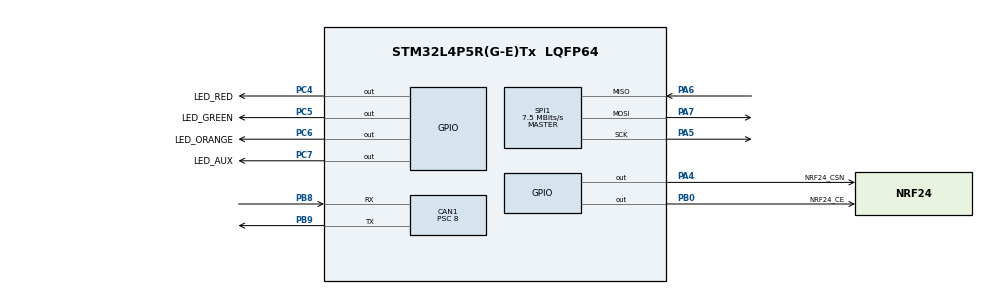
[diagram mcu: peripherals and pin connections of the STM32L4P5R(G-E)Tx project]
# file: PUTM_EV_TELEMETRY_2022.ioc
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ADC1.Channel-0\#ChannelRegularConversion=ADC_CHANNEL_VBAT
ADC1.NbrOfConversionFlag=1
ADC1.OffsetNumber-0\#ChannelRegularConversion=ADC_OFFSET_NONE
ADC1.Rank-0\#ChannelRegularConversion=1
ADC1.SamplingTime-0\#ChannelRegularConversion=ADC_SAMPLETIME_2CYCLES_5
ADC1.master=1
CAN1.BS1=CAN_BS1_12TQ
CAN1.BS2=CAN_BS2_2TQ
CAN1.CalculateBaudRate=999999
CAN1.CalculateTimeBit=1000
CAN1.CalculateTimeQuantum=66.66666666666667
CAN1.Mode=CAN_MODE_NORMAL
CAN1.Prescaler=8
CAN1.SJW=CAN_SJW_1TQ
Mcu.Family=STM32L4
Mcu.Name=STM32L4P5R(G-E)Tx
Mcu.Package=LQFP64
NVIC.CAN1_RX0_IRQn=true\:1\:0\:true\:false\:true\:true\:true\:true
NVIC.PriorityGroup=NVIC_PRIORITYGROUP_4
NVIC.TIM2_IRQn=true\:0\:0\:false\:false\:true\:true\:true\:true
NVIC.TIM3_IRQn=true\:0\:0\:false\:false\:true\:true\:true\:true
NVIC.TIM4_IRQn=true\:0\:0\:false\:false\:true\:true\:true\:true
NVIC.TIM5_IRQn=true\:0\:0\:false\:false\:true\:true\:true\:true
NVIC.TIM6_DAC_IRQn=true\:0\:0\:false\:false\:true\:true\:true\:true
PA13\ (JTMS/SWDIO).Mode=JTAG_5_pins
PA13\ (JTMS/SWDIO).Signal=SYS_JTMS-SWDIO
PA14\ (JTCK/SWCLK).Mode=JTAG_5_pins
PA14\ (JTCK/SWCLK).Signal=SYS_JTCK-SWCLK
PA15\ (JTDI).Mode=JTAG_5_pins
PA15\ (JTDI).Signal=SYS_JTDI
PA4.GPIO_Label=NRF24_CSN
PA4.Signal=GPIO_Output
PA5.Mode=Full_Duplex_Master
PA5.Signal=SPI1_SCK
PA6.Mode=Full_Duplex_Master
PA6.Signal=SPI1_MISO
PA7.Mode=Full_Duplex_Master
PA7.Signal=SPI1_MOSI
PB0.GPIO_Label=NRF24_CE
PB0.Signal=GPIO_Output
PB3\ (JTDO/TRACESWO).Mode=JTAG_5_pins
PB3\ (JTDO/TRACESWO).Signal=SYS_JTDO-SWO
PB4\ (NJTRST).Mode=JTAG_5_pins
PB4\ (NJTRST).Signal=SYS_JTRST
PB8.Mode=CAN_Activate
PB8.Signal=CAN1_RX
PB9.Mode=CAN_Activate
PB9.Signal=CAN1_TX
PC14-OSC32_IN\ (PC14).Signal=RCC_OSC32_IN
PC15-OSC32_OUT\ (PC15).Signal=RCC_OSC32_OUT
PC4.GPIO_Label=LED_RED
PC4.Signal=GPIO_Output
PC5.GPIO_Label=LED_GREEN
PC5.Signal=GPIO_Output
PC6.GPIO_Label=LED_ORANGE
PC6.Signal=GPIO_Output
PC7.GPIO_Label=LED_AUX
PC7.Signal=GPIO_Output
PH0-OSC_IN\ (PH0).Mode=HSE-External-Oscillator
PH0-OSC_IN\ (PH0).Signal=RCC_OSC_IN
PH1-OSC_OUT\ (PH1).Mode=HSE-External-Oscillator
PH1-OSC_OUT\ (PH1).Signal=RCC_OSC_OUT
ProjectManager.HeapSize=0x200
ProjectManager.StackSize=0x400
ProjectManager.TargetToolchain=STM32CubeIDE
RCC.ADCFreq_Value=32000000
RCC.AHBFreq_Value=120000000
RCC.APB1Freq_Value=120000000
RCC.APB1TimFreq_Value=120000000
RCC.APB2Freq_Value=120000000
RCC.APB2TimFreq_Value=120000000
RCC.CortexFreq_Value=120000000
RCC.HCLKFreq_Value=120000000
RCC.HSE_VALUE=24576000
RCC.HSI48_VALUE=48000000
RCC.HSI_VALUE=16000000
RCC.LSE_VALUE=32768
RCC.MSI_VALUE=4000000
RCC.PLLN=60
RCC.PLLSAI1N=16
RCC.PREFETCH_ENABLE=1
RCC.SYSCLKFreq_VALUE=120000000
RCC.SYSCLKSource=RCC_SYSCLKSOURCE_PLLCLK
RCC.USBFreq_Value=32000000
RCC.VCOOutputFreq_Value=240000000
RTC.Format=RTC_FORMAT_BIN
RTC.Hours=17
RTC.Minutes=13
SPI1.BaudRatePrescaler=SPI_BAUDRATEPRESCALER_16
SPI1.CalculateBaudRate=7.5 MBits/s
SPI1.DataSize=SPI_DATASIZE_8BIT
SPI1.Direction=SPI_DIRECTION_2LINES
SPI1.Mode=SPI_MODE_MASTER
SPI1.VirtualType=VM_MASTER
TIM2.AutoReloadPreload=TIM_AUTORELOAD_PRELOAD_ENABLE
TIM2.Period=10000
TIM2.Prescaler=12000-1
TIM3.AutoReloadPreload=TIM_AUTORELOAD_PRELOAD_ENABLE
TIM3.Period=100
TIM3.Prescaler=12000-1
TIM4.AutoReloadPreload=TIM_AUTORELOAD_PRELOAD_ENABLE
TIM4.Period=200
TIM4.Prescaler=12000-1
TIM5.AutoReloadPreload=TIM_AUTORELOAD_PRELOAD_ENABLE
TIM5.Period=300
TIM5.Prescaler=12000-1
TIM6.AutoReloadPreload=TIM_AUTORELOAD_PRELOAD_ENABLE
TIM6.Period=5000
TIM6.Prescaler=1200-1
TIM7.AutoReloadPreload=TIM_AUTORELOAD_PRELOAD_ENABLE
TIM7.Prescaler=120-1
VP_ADC1_Vbat_Input.Mode=IN-Vbat
VP_RTC_VS_RTC_Activate.Mode=RTC_Enabled
VP_RTC_VS_RTC_Calendar.Mode=RTC_Calendar
VP_TIM2_VS_ClockSourceINT.Mode=Internal
VP_TIM3_VS_ClockSourceINT.Mode=Internal
VP_TIM4_VS_ClockSourceINT.Mode=Internal
VP_TIM5_VS_ClockSourceINT.Mode=Internal
VP_TIM6_VS_ClockSourceINT.Mode=Enable_Timer
VP_TIM7_VS_ClockSourceINT.Mode=Enable_Timer
board=custom

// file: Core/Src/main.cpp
/* USER CODE BEGIN Header */
/**
 ******************************************************************************
 * @file           : main.c
 * @brief          : Main program body
 ******************************************************************************
 * @attention
 *
 * <h2><center>&copy; Copyright (c) 2022 STMicroelectronics.
 * All rights reserved.</center></h2>
 *
 * This software component is licensed by ST under BSD 3-Clause license,
 * the "License"; You may not use this file except in compliance with the
 * License. You may obtain a copy of the License at:
 *                        opensource.org/licenses/BSD-3-Clause
 *
 ******************************************************************************
 */
/* USER CODE END Header */
#include "main.h"

/* USER CODE BEGIN Includes */
#include "Data_Handling.hpp"
#include "LEDs.hpp"
#include "Radio_Control.hpp"
#include "etl/circular_buffer.h"
#include <vector>
/* USER CODE END Includes */

/* USER CODE BEGIN PTD */
CAN_FilterTypeDef flitr1;
CAN_RxHeaderTypeDef RxHeader_CAN1;
/* USER CODE END PTD */

ADC_HandleTypeDef hadc1;

CAN_HandleTypeDef hcan1;

RTC_HandleTypeDef hrtc;

SPI_HandleTypeDef hspi1;

TIM_HandleTypeDef htim2;
TIM_HandleTypeDef htim3;
TIM_HandleTypeDef htim4;
TIM_HandleTypeDef htim5;
TIM_HandleTypeDef htim6;
TIM_HandleTypeDef htim7;

void SystemClock_Config(void);
static void MX_GPIO_Init(void);
static void MX_CAN1_Init(void);
static void MX_SPI1_Init(void);
static void MX_TIM2_Init(void);
static void MX_RTC_Init(void);
static void MX_ADC1_Init(void);
static void MX_TIM3_Init(void);
static void MX_TIM4_Init(void);
static void MX_TIM5_Init(void);
static void MX_TIM6_Init(void);
static void MX_TIM7_Init(void);

/* USER CODE BEGIN 0 */
Data_management handler1;
HeartBeat hb1;
const bool Frame_By_Frame = false;
/* USER CODE END 0 */

int main(void)
{

  /* MCU Configuration--------------------------------------------------------*/

  /* Reset of all peripherals, Initializes the Flash interface and the Systick. */
  HAL_Init();

  /* Configure the system clock */
  SystemClock_Config();

  /* Initialize all configured peripherals */
  MX_GPIO_Init();
  MX_CAN1_Init();
  MX_SPI1_Init();
  MX_TIM2_Init();
  MX_RTC_Init();
  MX_ADC1_Init();
  MX_TIM3_Init();
  MX_TIM4_Init();
  MX_TIM5_Init();
  MX_TIM6_Init();
  MX_TIM7_Init();
  /* USER CODE BEGIN 2 */

    Clear_All();

    Start();

    Open_Filter();

    CAN_Init();

    if (Setup_Radio_As_Transmiter() == false)
    {
        Set_Error();
        Set_All();
        Error_Handler();
        //handler1.Pass_States(RADIO_ERROR);
    }
    else
    {
        Set_OK();
    }

    if (Frame_By_Frame == true)
    {
        // HAL_TIM_Base_Start_IT(&htim2);
        hb1 = HeartBeat::FRAME_BY_FRAME;
    }
    else
    {
        //HAL_TIM_Base_Start_IT(&htim2);
        HAL_TIM_Base_Start_IT(&htim3);
        HAL_TIM_Base_Start_IT(&htim4);
        HAL_TIM_Base_Start_IT(&htim5);
        HAL_TIM_Base_Start_IT(&htim6);
        hb1 = HeartBeat::DEFAULT;
    }
  /* USER CODE END 2 */

  /* Infinite loop */
    while (1)
    {

    /* USER CODE BEGIN 3 */
        /*
         * Regular state of the code, used to receive, pack and send data
         */

        switch (hb1)
        {
            case HeartBeat::Buffer1:

                Send_Data(handler1.Check_Buffer100hz());
                HAL_Delay(1);
                Send_Data(handler1.Check_Buffer_Aq());
                HAL_Delay(1);
                handler1.Clear_msg1();
                break;

            case HeartBeat::Buffer2:

                Send_Data(handler1.Check_Buffer50hz());
                HAL_Delay(1);
                break;

            case HeartBeat::Buffer3:

                Send_Data(handler1.Check_Buffer10hz());
                HAL_Delay(1);
            	if(handler1.timer_buffer.size() > 0)
            	{
            		Send_Data(handler1.timer_buffer.back());
            		handler1.timer_buffer.pop_back();
            	}
                break;

            case HeartBeat::Buffer4:

            	Send_Data(handler1.Check_Buffer1hz());
            	HAL_Delay(1);

            case HeartBeat::DEFAULT:

                break;
        }
    }
  /* USER CODE END 3 */
}

void SystemClock_Config(void)
{
  RCC_OscInitTypeDef RCC_OscInitStruct = {0};
  RCC_ClkInitTypeDef RCC_ClkInitStruct = {0};

  /** Configure the main internal regulator output voltage
  */
  if (HAL_PWREx_ControlVoltageScaling(PWR_REGULATOR_VOLTAGE_SCALE1_BOOST) != HAL_OK)
  {
    Error_Handler();
  }

  /** Initializes the RCC Oscillators according to the specified parameters
  * in the RCC_OscInitTypeDef structure.
  */
  RCC_OscInitStruct.OscillatorType = RCC_OSCILLATORTYPE_LSI|RCC_OSCILLATORTYPE_HSE;
  RCC_OscInitStruct.HSEState = RCC_HSE_ON;
  RCC_OscInitStruct.LSIState = RCC_LSI_ON;
  RCC_OscInitStruct.PLL.PLLState = RCC_PLL_ON;
  RCC_OscInitStruct.PLL.PLLSource = RCC_PLLSOURCE_HSE;
  RCC_OscInitStruct.PLL.PLLM = 4;
  RCC_OscInitStruct.PLL.PLLN = 30;
  RCC_OscInitStruct.PLL.PLLP = RCC_PLLP_DIV2;
  RCC_OscInitStruct.PLL.PLLQ = RCC_PLLQ_DIV2;
  RCC_OscInitStruct.PLL.PLLR = RCC_PLLR_DIV2;
  if (HAL_RCC_OscConfig(&RCC_OscInitStruct) != HAL_OK)
  {
    Error_Handler();
  }

  /** Initializes the CPU, AHB and APB buses clocks
  */
  RCC_ClkInitStruct.ClockType = RCC_CLOCKTYPE_HCLK|RCC_CLOCKTYPE_SYSCLK
                              |RCC_CLOCKTYPE_PCLK1|RCC_CLOCKTYPE_PCLK2;
  RCC_ClkInitStruct.SYSCLKSource = RCC_SYSCLKSOURCE_PLLCLK;
  RCC_ClkInitStruct.AHBCLKDivider = RCC_SYSCLK_DIV1;
  RCC_ClkInitStruct.APB1CLKDivider = RCC_HCLK_DIV1;
  RCC_ClkInitStruct.APB2CLKDivider = RCC_HCLK_DIV1;

  if (HAL_RCC_ClockConfig(&RCC_ClkInitStruct, FLASH_LATENCY_5) != HAL_OK)
  {
    Error_Handler();
  }
}

static void MX_ADC1_Init(void)
{

  ADC_MultiModeTypeDef multimode = {0};
  ADC_ChannelConfTypeDef sConfig = {0};

  /** Common config
  */
  hadc1.Instance = ADC1;
  hadc1.Init.ClockPrescaler = ADC_CLOCK_ASYNC_DIV1;
  hadc1.Init.Resolution = ADC_RESOLUTION_12B;
  hadc1.Init.DataAlign = ADC_DATAALIGN_RIGHT;
  hadc1.Init.ScanConvMode = ADC_SCAN_DISABLE;
  hadc1.Init.EOCSelection = ADC_EOC_SINGLE_CONV;
  hadc1.Init.LowPowerAutoWait = DISABLE;
  hadc1.Init.ContinuousConvMode = DISABLE;
  hadc1.Init.NbrOfConversion = 1;
  hadc1.Init.DiscontinuousConvMode = DISABLE;
  hadc1.Init.ExternalTrigConv = ADC_SOFTWARE_START;
  hadc1.Init.ExternalTrigConvEdge = ADC_EXTERNALTRIGCONVEDGE_NONE;
  hadc1.Init.DMAContinuousRequests = DISABLE;
  hadc1.Init.Overrun = ADC_OVR_DATA_PRESERVED;
  hadc1.Init.OversamplingMode = DISABLE;
  hadc1.Init.DFSDMConfig = ADC_DFSDM_MODE_ENABLE;
  if (HAL_ADC_Init(&hadc1) != HAL_OK)
  {
    Error_Handler();
  }

  /** Configure the ADC multi-mode
  */
  multimode.Mode = ADC_MODE_INDEPENDENT;
  if (HAL_ADCEx_MultiModeConfigChannel(&hadc1, &multimode) != HAL_OK)
  {
    Error_Handler();
  }

  /** Configure Regular Channel
  */
  sConfig.Channel = ADC_CHANNEL_VBAT;
  sConfig.Rank = ADC_REGULAR_RANK_1;
  sConfig.SamplingTime = ADC_SAMPLETIME_2CYCLES_5;
  sConfig.SingleDiff = ADC_SINGLE_ENDED;
  sConfig.OffsetNumber = ADC_OFFSET_NONE;
  sConfig.Offset = 0;
  if (HAL_ADC_ConfigChannel(&hadc1, &sConfig) != HAL_OK)
  {
    Error_Handler();
  }

}

static void MX_CAN1_Init(void)
{

  hcan1.Instance = CAN1;
  hcan1.Init.Prescaler = 8;
  hcan1.Init.Mode = CAN_MODE_NORMAL;
  hcan1.Init.SyncJumpWidth = CAN_SJW_1TQ;
  hcan1.Init.TimeSeg1 = CAN_BS1_12TQ;
  hcan1.Init.TimeSeg2 = CAN_BS2_2TQ;
  hcan1.Init.TimeTriggeredMode = DISABLE;
  hcan1.Init.AutoBusOff = DISABLE;
  hcan1.Init.AutoWakeUp = DISABLE;
  hcan1.Init.AutoRetransmission = DISABLE;
  hcan1.Init.ReceiveFifoLocked = DISABLE;
  hcan1.Init.TransmitFifoPriority = DISABLE;
  if (HAL_CAN_Init(&hcan1) != HAL_OK)
  {
    Error_Handler();
  }

}

static void MX_RTC_Init(void)
{

  RTC_TimeTypeDef sTime = {0};
  RTC_DateTypeDef sDate = {0};

  /** Initialize RTC Only
  */
  hrtc.Instance = RTC;
  hrtc.Init.HourFormat = RTC_HOURFORMAT_24;
  hrtc.Init.AsynchPrediv = 127;
  hrtc.Init.SynchPrediv = 255;
  hrtc.Init.OutPut = RTC_OUTPUT_DISABLE;
  hrtc.Init.OutPutRemap = RTC_OUTPUT_REMAP_NONE;
  hrtc.Init.OutPutPolarity = RTC_OUTPUT_POLARITY_HIGH;
  hrtc.Init.OutPutType = RTC_OUTPUT_TYPE_OPENDRAIN;
  hrtc.Init.BinMode = RTC_BINARY_NONE;
  if (HAL_RTC_Init(&hrtc) != HAL_OK)
  {
    Error_Handler();
  }

  /** Initialize RTC and set the Time and Date
  */
  sTime.Hours = 17;
  sTime.Minutes = 13;
  sTime.Seconds = 0;
  sTime.DayLightSaving = RTC_DAYLIGHTSAVING_NONE;
  sTime.StoreOperation = RTC_STOREOPERATION_RESET;
  if (HAL_RTC_SetTime(&hrtc, &sTime, RTC_FORMAT_BIN) != HAL_OK)
  {
    Error_Handler();
  }
  sDate.WeekDay = RTC_WEEKDAY_MONDAY;
  sDate.Month = RTC_MONTH_JANUARY;
  sDate.Date = 1;
  sDate.Year = 0;

  if (HAL_RTC_SetDate(&hrtc, &sDate, RTC_FORMAT_BIN) != HAL_OK)
  {
    Error_Handler();
  }

}

static void MX_SPI1_Init(void)
{

  /* SPI1 parameter configuration*/
  hspi1.Instance = SPI1;
  hspi1.Init.Mode = SPI_MODE_MASTER;
  hspi1.Init.Direction = SPI_DIRECTION_2LINES;
  hspi1.Init.DataSize = SPI_DATASIZE_8BIT;
  hspi1.Init.CLKPolarity = SPI_POLARITY_LOW;
  hspi1.Init.CLKPhase = SPI_PHASE_1EDGE;
  hspi1.Init.NSS = SPI_NSS_SOFT;
  hspi1.Init.BaudRatePrescaler = SPI_BAUDRATEPRESCALER_16;
  hspi1.Init.FirstBit = SPI_FIRSTBIT_MSB;
  hspi1.Init.TIMode = SPI_TIMODE_DISABLE;
  hspi1.Init.CRCCalculation = SPI_CRCCALCULATION_DISABLE;
  hspi1.Init.CRCPolynomial = 7;
  hspi1.Init.CRCLength = SPI_CRC_LENGTH_DATASIZE;
  hspi1.Init.NSSPMode = SPI_NSS_PULSE_ENABLE;
  if (HAL_SPI_Init(&hspi1) != HAL_OK)
  {
    Error_Handler();
  }

}

static void MX_TIM2_Init(void)
{

  TIM_ClockConfigTypeDef sClockSourceConfig = {0};
  TIM_MasterConfigTypeDef sMasterConfig = {0};

  htim2.Instance = TIM2;
  htim2.Init.Prescaler = 12000-1;
  htim2.Init.CounterMode = TIM_COUNTERMODE_UP;
  htim2.Init.Period = 10000;
  htim2.Init.ClockDivision = TIM_CLOCKDIVISION_DIV1;
  htim2.Init.AutoReloadPreload = TIM_AUTORELOAD_PRELOAD_ENABLE;
  if (HAL_TIM_Base_Init(&htim2) != HAL_OK)
  {
    Error_Handler();
  }
  sClockSourceConfig.ClockSource = TIM_CLOCKSOURCE_INTERNAL;
  if (HAL_TIM_ConfigClockSource(&htim2, &sClockSourceConfig) != HAL_OK)
  {
    Error_Handler();
  }
  sMasterConfig.MasterOutputTrigger = TIM_TRGO_RESET;
  sMasterConfig.MasterSlaveMode = TIM_MASTERSLAVEMODE_DISABLE;
  if (HAL_TIMEx_MasterConfigSynchronization(&htim2, &sMasterConfig) != HAL_OK)
  {
    Error_Handler();
  }

}

static void MX_TIM3_Init(void)
{

  TIM_ClockConfigTypeDef sClockSourceConfig = {0};
  TIM_MasterConfigTypeDef sMasterConfig = {0};

  htim3.Instance = TIM3;
  htim3.Init.Prescaler = 12000-1;
  htim3.Init.CounterMode = TIM_COUNTERMODE_UP;
  htim3.Init.Period = 100;
  htim3.Init.ClockDivision = TIM_CLOCKDIVISION_DIV1;
  htim3.Init.AutoReloadPreload = TIM_AUTORELOAD_PRELOAD_ENABLE;
  if (HAL_TIM_Base_Init(&htim3) != HAL_OK)
  {
    Error_Handler();
  }
  sClockSourceConfig.ClockSource = TIM_CLOCKSOURCE_INTERNAL;
  if (HAL_TIM_ConfigClockSource(&htim3, &sClockSourceConfig) != HAL_OK)
  {
    Error_Handler();
  }
  sMasterConfig.MasterOutputTrigger = TIM_TRGO_RESET;
  sMasterConfig.MasterSlaveMode = TIM_MASTERSLAVEMODE_DISABLE;
  if (HAL_TIMEx_MasterConfigSynchronization(&htim3, &sMasterConfig) != HAL_OK)
  {
    Error_Handler();
  }

}

static void MX_TIM4_Init(void)
{

  TIM_ClockConfigTypeDef sClockSourceConfig = {0};
  TIM_MasterConfigTypeDef sMasterConfig = {0};

  htim4.Instance = TIM4;
  htim4.Init.Prescaler = 12000-1;
  htim4.Init.CounterMode = TIM_COUNTERMODE_UP;
  htim4.Init.Period = 200;
  htim4.Init.ClockDivision = TIM_CLOCKDIVISION_DIV1;
  htim4.Init.AutoReloadPreload = TIM_AUTORELOAD_PRELOAD_ENABLE;
  if (HAL_TIM_Base_Init(&htim4) != HAL_OK)
  {
    Error_Handler();
  }
  sClockSourceConfig.ClockSource = TIM_CLOCKSOURCE_INTERNAL;
  if (HAL_TIM_ConfigClockSource(&htim4, &sClockSourceConfig) != HAL_OK)
  {
    Error_Handler();
  }
  sMasterConfig.MasterOutputTrigger = TIM_TRGO_RESET;
  sMasterConfig.MasterSlaveMode = TIM_MASTERSLAVEMODE_DISABLE;
  if (HAL_TIMEx_MasterConfigSynchronization(&htim4, &sMasterConfig) != HAL_OK)
  {
    Error_Handler();
  }

}

static void MX_TIM5_Init(void)
{

  TIM_ClockConfigTypeDef sClockSourceConfig = {0};
  TIM_MasterConfigTypeDef sMasterConfig = {0};

  htim5.Instance = TIM5;
  htim5.Init.Prescaler = 12000-1;
  htim5.Init.CounterMode = TIM_COUNTERMODE_UP;
  htim5.Init.Period = 300;
  htim5.Init.ClockDivision = TIM_CLOCKDIVISION_DIV1;
  htim5.Init.AutoReloadPreload = TIM_AUTORELOAD_PRELOAD_ENABLE;
  if (HAL_TIM_Base_Init(&htim5) != HAL_OK)
  {
    Error_Handler();
  }
  sClockSourceConfig.ClockSource = TIM_CLOCKSOURCE_INTERNAL;
  if (HAL_TIM_ConfigClockSource(&htim5, &sClockSourceConfig) != HAL_OK)
  {
    Error_Handler();
  }
  sMasterConfig.MasterOutputTrigger = TIM_TRGO_RESET;
  sMasterConfig.MasterSlaveMode = TIM_MASTERSLAVEMODE_DISABLE;
  if (HAL_TIMEx_MasterConfigSynchronization(&htim5, &sMasterConfig) != HAL_OK)
  {
    Error_Handler();
  }

}

static void MX_TIM6_Init(void)
{

  TIM_MasterConfigTypeDef sMasterConfig = {0};

  htim6.Instance = TIM6;
  htim6.Init.Prescaler = 1200-1;
  htim6.Init.CounterMode = TIM_COUNTERMODE_UP;
  htim6.Init.Period = 5000;
  htim6.Init.AutoReloadPreload = TIM_AUTORELOAD_PRELOAD_ENABLE;
  if (HAL_TIM_Base_Init(&htim6) != HAL_OK)
  {
    Error_Handler();
  }
  sMasterConfig.MasterOutputTrigger = TIM_TRGO_RESET;
  sMasterConfig.MasterSlaveMode = TIM_MASTERSLAVEMODE_DISABLE;
  if (HAL_TIMEx_MasterConfigSynchronization(&htim6, &sMasterConfig) != HAL_OK)
  {
    Error_Handler();
  }

}

static void MX_TIM7_Init(void)
{

  TIM_MasterConfigTypeDef sMasterConfig = {0};

  htim7.Instance = TIM7;
  htim7.Init.Prescaler = 120-1;
  htim7.Init.CounterMode = TIM_COUNTERMODE_UP;
  htim7.Init.Period = 65535;
  htim7.Init.AutoReloadPreload = TIM_AUTORELOAD_PRELOAD_ENABLE;
  if (HAL_TIM_Base_Init(&htim7) != HAL_OK)
  {
    Error_Handler();
  }
  sMasterConfig.MasterOutputTrigger = TIM_TRGO_RESET;
  sMasterConfig.MasterSlaveMode = TIM_MASTERSLAVEMODE_DISABLE;
  if (HAL_TIMEx_MasterConfigSynchronization(&htim7, &sMasterConfig) != HAL_OK)
  {
    Error_Handler();
  }

}

static void MX_GPIO_Init(void)
{
  GPIO_InitTypeDef GPIO_InitStruct = {0};

  /* GPIO Ports Clock Enable */
  __HAL_RCC_GPIOC_CLK_ENABLE();
  __HAL_RCC_GPIOH_CLK_ENABLE();
  __HAL_RCC_GPIOA_CLK_ENABLE();
  __HAL_RCC_GPIOB_CLK_ENABLE();

  /*Configure GPIO pin Output Level */
  HAL_GPIO_WritePin(NRF24_CSN_GPIO_Port, NRF24_CSN_Pin, GPIO_PIN_RESET);

  /*Configure GPIO pin Output Level */
  HAL_GPIO_WritePin(GPIOC, LED_RED_Pin|LED_GREEN_Pin|LED_ORANGE_Pin|LED_AUX_Pin, GPIO_PIN_RESET);

  /*Configure GPIO pin Output Level */
  HAL_GPIO_WritePin(NRF24_CE_GPIO_Port, NRF24_CE_Pin, GPIO_PIN_RESET);

  /*Configure GPIO pin : NRF24_CSN_Pin */
  GPIO_InitStruct.Pin = NRF24_CSN_Pin;
  GPIO_InitStruct.Mode = GPIO_MODE_OUTPUT_PP;
  GPIO_InitStruct.Pull = GPIO_NOPULL;
  GPIO_InitStruct.Speed = GPIO_SPEED_FREQ_LOW;
  HAL_GPIO_Init(NRF24_CSN_GPIO_Port, &GPIO_InitStruct);

  /*Configure GPIO pins : LED_RED_Pin LED_GREEN_Pin LED_ORANGE_Pin LED_AUX_Pin */
  GPIO_InitStruct.Pin = LED_RED_Pin|LED_GREEN_Pin|LED_ORANGE_Pin|LED_AUX_Pin;
  GPIO_InitStruct.Mode = GPIO_MODE_OUTPUT_PP;
  GPIO_InitStruct.Pull = GPIO_NOPULL;
  GPIO_InitStruct.Speed = GPIO_SPEED_FREQ_LOW;
  HAL_GPIO_Init(GPIOC, &GPIO_InitStruct);

  /*Configure GPIO pin : NRF24_CE_Pin */
  GPIO_InitStruct.Pin = NRF24_CE_Pin;
  GPIO_InitStruct.Mode = GPIO_MODE_OUTPUT_PP;
  GPIO_InitStruct.Pull = GPIO_NOPULL;
  GPIO_InitStruct.Speed = GPIO_SPEED_FREQ_LOW;
  HAL_GPIO_Init(NRF24_CE_GPIO_Port, &GPIO_InitStruct);

}

void Error_Handler(void)
{
  /* USER CODE BEGIN Error_Handler_Debug */
    /* User can add his own implementation to report the HAL error return state
     */
    __disable_irq();
    while (1)
    {
    }
  /* USER CODE END Error_Handler_Debug */
}

#ifdef  USE_FULL_ASSERT
/**
  * @brief  Reports the name of the source file and the source line number
  *         where the assert_param error has occurred.
  * @param  file: pointer to the source file name
  * @param  line: assert_param error line source number
  * @retval None
  */
void assert_failed(uint8_t *file, uint32_t line)
{
  /* USER CODE BEGIN 6 */
    /* User can add his own implementation to report the file name and line
 number, ex: printf("Wrong parameters value: file %s on line %d\r\n", file,
 line) */
  /* USER CODE END 6 */
}
#endif /* USE_FULL_ASSERT */
